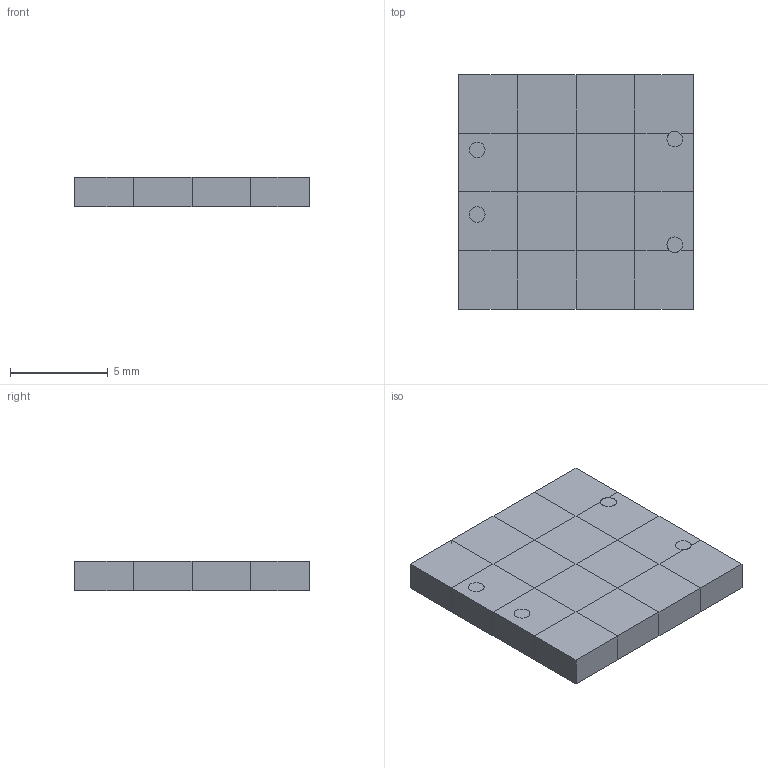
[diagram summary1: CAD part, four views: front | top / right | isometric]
STEP (ISO 10303-21) file: header records copied from the file, then geometry measured from it (millimetres).
FILE_DESCRIPTION(('Open CASCADE Model'),'2;1');
FILE_NAME('Open CASCADE Shape Model','2026-11-27T10:07:31',('Author'),( 'Open CASCADE'),'Open CASCADE STEP processor 7.9','Open CASCADE 7.9' ,'Unknown');
FILE_SCHEMA(('AUTOMOTIVE_DESIGN { 1 0 10303 214 1 1 1 1 }'));
Length unit declared in the file: millimetre
Products named in the file (3): manifold_N9; fluid; solid
Assembly tree (2 placements, depth 2):
  manifold_N9
    fluid
    solid
Bounding box: 12 x 12 x 1.5 mm (x, y, z)
Volume: 216 mm3; surface area: 1498.3 mm2
Topology: 2 solids, 2 shells, 1328 faces, 4594 edges, 2558 vertices
Faces by surface type: plane 1320, cylinder 8
Full cylindrical faces by diameter (mm): 0.8 x8
Entity records: 108008 total; most frequent: CARTESIAN_POINT 18681, DIRECTION 16226, LINE 13268, VECTOR 13268, ORIENTED_EDGE 9196, PCURVE 9188, DEFINITIONAL_REPRESENTATION 9188, EDGE_CURVE 4594
One B-rep face of a CAD part: STEP entity #57526.
In plain terms, the planar face has unit normal (0, 0, 1).
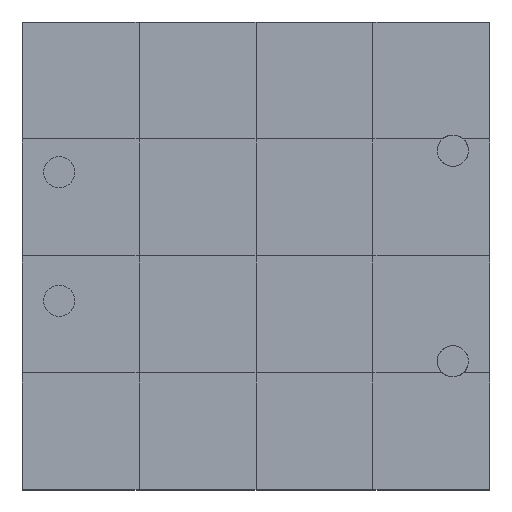
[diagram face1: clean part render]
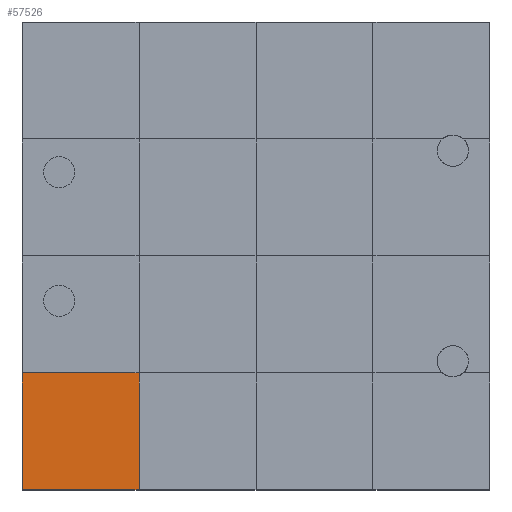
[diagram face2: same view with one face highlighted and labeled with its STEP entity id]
Its self-contained STEP definition (entity closure, numbers rounded to 3 decimals):
#57337 = VERTEX_POINT('',#57338);
#57338 = CARTESIAN_POINT('',(0.,0.,1.5));
#57345 = PLANE('',#57346);
#57346 = AXIS2_PLACEMENT_3D('',#57347,#57348,#57349);
#57347 = CARTESIAN_POINT('',(0.,0.,0.));
#57348 = DIRECTION('',(1.,0.,-0.));
#57349 = DIRECTION('',(0.,0.,1.));
#57357 = PLANE('',#57358);
#57358 = AXIS2_PLACEMENT_3D('',#57359,#57360,#57361);
#57359 = CARTESIAN_POINT('',(0.,0.,0.));
#57360 = DIRECTION('',(-0.,1.,0.));
#57361 = DIRECTION('',(0.,0.,1.));
#57398 = VERTEX_POINT('',#57399);
#57399 = CARTESIAN_POINT('',(0.,3.,1.5));
#57425 = EDGE_CURVE('',#57337,#57398,#57426,.T.);
#57426 = SURFACE_CURVE('',#57427,(#57431,#57438),.PCURVE_S1.);
#57427 = LINE('',#57428,#57429);
#57428 = CARTESIAN_POINT('',(0.,0.,1.5));
#57429 = VECTOR('',#57430,1.);
#57430 = DIRECTION('',(-0.,1.,0.));
#57431 = PCURVE('',#57345,#57432);
#57432 = DEFINITIONAL_REPRESENTATION('',(#57433),#57437);
#57433 = LINE('',#57434,#57435);
#57434 = CARTESIAN_POINT('',(1.5,0.));
#57435 = VECTOR('',#57436,1.);
#57436 = DIRECTION('',(0.,-1.));
#57437 = ( GEOMETRIC_REPRESENTATION_CONTEXT(2) 
PARAMETRIC_REPRESENTATION_CONTEXT() REPRESENTATION_CONTEXT('2D SPACE',''
  ) );
#57438 = PCURVE('',#57439,#57444);
#57439 = PLANE('',#57440);
#57440 = AXIS2_PLACEMENT_3D('',#57441,#57442,#57443);
#57441 = CARTESIAN_POINT('',(0.,0.,1.5));
#57442 = DIRECTION('',(0.,0.,1.));
#57443 = DIRECTION('',(1.,0.,-0.));
#57444 = DEFINITIONAL_REPRESENTATION('',(#57445),#57449);
#57445 = LINE('',#57446,#57447);
#57446 = CARTESIAN_POINT('',(0.,0.));
#57447 = VECTOR('',#57448,1.);
#57448 = DIRECTION('',(0.,1.));
#57449 = ( GEOMETRIC_REPRESENTATION_CONTEXT(2) 
PARAMETRIC_REPRESENTATION_CONTEXT() REPRESENTATION_CONTEXT('2D SPACE',''
  ) );
#57478 = EDGE_CURVE('',#57337,#57479,#57481,.T.);
#57479 = VERTEX_POINT('',#57480);
#57480 = CARTESIAN_POINT('',(3.,0.,1.5));
#57481 = SURFACE_CURVE('',#57482,(#57486,#57493),.PCURVE_S1.);
#57482 = LINE('',#57483,#57484);
#57483 = CARTESIAN_POINT('',(0.,0.,1.5));
#57484 = VECTOR('',#57485,1.);
#57485 = DIRECTION('',(1.,0.,-0.));
#57486 = PCURVE('',#57357,#57487);
#57487 = DEFINITIONAL_REPRESENTATION('',(#57488),#57492);
#57488 = LINE('',#57489,#57490);
#57489 = CARTESIAN_POINT('',(1.5,0.));
#57490 = VECTOR('',#57491,1.);
#57491 = DIRECTION('',(0.,1.));
#57492 = ( GEOMETRIC_REPRESENTATION_CONTEXT(2) 
PARAMETRIC_REPRESENTATION_CONTEXT() REPRESENTATION_CONTEXT('2D SPACE',''
  ) );
#57493 = PCURVE('',#57439,#57494);
#57494 = DEFINITIONAL_REPRESENTATION('',(#57495),#57499);
#57495 = LINE('',#57496,#57497);
#57496 = CARTESIAN_POINT('',(0.,0.));
#57497 = VECTOR('',#57498,1.);
#57498 = DIRECTION('',(1.,0.));
#57499 = ( GEOMETRIC_REPRESENTATION_CONTEXT(2) 
PARAMETRIC_REPRESENTATION_CONTEXT() REPRESENTATION_CONTEXT('2D SPACE',''
  ) );
#57526 = ADVANCED_FACE('',(#57527),#57439,.T.);
#57527 = FACE_BOUND('',#57528,.T.);
#57528 = EDGE_LOOP('',(#57529,#57530,#57531,#57559));
#57529 = ORIENTED_EDGE('',*,*,#57425,.F.);
#57530 = ORIENTED_EDGE('',*,*,#57478,.T.);
#57531 = ORIENTED_EDGE('',*,*,#57532,.T.);
#57532 = EDGE_CURVE('',#57479,#57533,#57535,.T.);
#57533 = VERTEX_POINT('',#57534);
#57534 = CARTESIAN_POINT('',(3.,3.,1.5));
#57535 = SURFACE_CURVE('',#57536,(#57540,#57547),.PCURVE_S1.);
#57536 = LINE('',#57537,#57538);
#57537 = CARTESIAN_POINT('',(3.,0.,1.5));
#57538 = VECTOR('',#57539,1.);
#57539 = DIRECTION('',(-0.,1.,0.));
#57540 = PCURVE('',#57439,#57541);
#57541 = DEFINITIONAL_REPRESENTATION('',(#57542),#57546);
#57542 = LINE('',#57543,#57544);
#57543 = CARTESIAN_POINT('',(3.,0.));
#57544 = VECTOR('',#57545,1.);
#57545 = DIRECTION('',(0.,1.));
#57546 = ( GEOMETRIC_REPRESENTATION_CONTEXT(2) 
PARAMETRIC_REPRESENTATION_CONTEXT() REPRESENTATION_CONTEXT('2D SPACE',''
  ) );
#57547 = PCURVE('',#57548,#57553);
#57548 = PLANE('',#57549);
#57549 = AXIS2_PLACEMENT_3D('',#57550,#57551,#57552);
#57550 = CARTESIAN_POINT('',(3.,0.,1.5));
#57551 = DIRECTION('',(0.,0.,1.));
#57552 = DIRECTION('',(1.,0.,-0.));
#57553 = DEFINITIONAL_REPRESENTATION('',(#57554),#57558);
#57554 = LINE('',#57555,#57556);
#57555 = CARTESIAN_POINT('',(0.,0.));
#57556 = VECTOR('',#57557,1.);
#57557 = DIRECTION('',(0.,1.));
#57558 = ( GEOMETRIC_REPRESENTATION_CONTEXT(2) 
PARAMETRIC_REPRESENTATION_CONTEXT() REPRESENTATION_CONTEXT('2D SPACE',''
  ) );
#57559 = ORIENTED_EDGE('',*,*,#57560,.F.);
#57560 = EDGE_CURVE('',#57398,#57533,#57561,.T.);
#57561 = SURFACE_CURVE('',#57562,(#57566,#57573),.PCURVE_S1.);
#57562 = LINE('',#57563,#57564);
#57563 = CARTESIAN_POINT('',(0.,3.,1.5));
#57564 = VECTOR('',#57565,1.);
#57565 = DIRECTION('',(1.,0.,-0.));
#57566 = PCURVE('',#57439,#57567);
#57567 = DEFINITIONAL_REPRESENTATION('',(#57568),#57572);
#57568 = LINE('',#57569,#57570);
#57569 = CARTESIAN_POINT('',(0.,3.));
#57570 = VECTOR('',#57571,1.);
#57571 = DIRECTION('',(1.,0.));
#57572 = ( GEOMETRIC_REPRESENTATION_CONTEXT(2) 
PARAMETRIC_REPRESENTATION_CONTEXT() REPRESENTATION_CONTEXT('2D SPACE',''
  ) );
#57573 = PCURVE('',#57574,#57579);
#57574 = PLANE('',#57575);
#57575 = AXIS2_PLACEMENT_3D('',#57576,#57577,#57578);
#57576 = CARTESIAN_POINT('',(0.,3.,1.5));
#57577 = DIRECTION('',(0.,0.,1.));
#57578 = DIRECTION('',(1.,0.,-0.));
#57579 = DEFINITIONAL_REPRESENTATION('',(#57580),#57584);
#57580 = LINE('',#57581,#57582);
#57581 = CARTESIAN_POINT('',(0.,0.));
#57582 = VECTOR('',#57583,1.);
#57583 = DIRECTION('',(1.,0.));
#57584 = ( GEOMETRIC_REPRESENTATION_CONTEXT(2) 
PARAMETRIC_REPRESENTATION_CONTEXT() REPRESENTATION_CONTEXT('2D SPACE',''
  ) );
